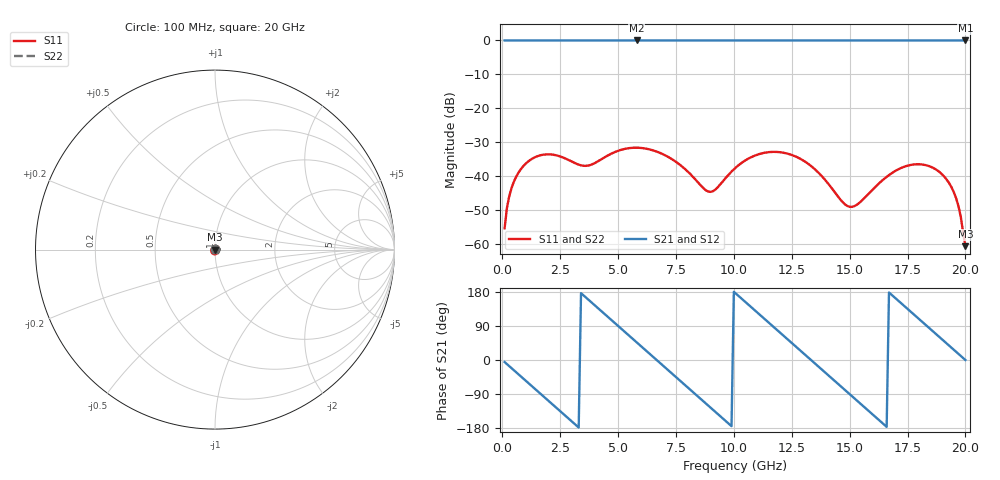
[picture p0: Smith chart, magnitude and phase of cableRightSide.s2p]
! File created by SignalIntegrity v1.5.2: Signal and Power Integrity Tools
! https://github.com/Nubis-Communications/SignalIntegrity
# MHz S MA R 50.0
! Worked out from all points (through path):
!   200 points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, 100 MHz to 20 GHz, reference 50 ohm
!   highest |S21| = 0.00 dB at 20 GHz (marker M1); lowest = 0.0 dB at 5.8 GHz (marker M2)
!   group delay of S21, straight-line fit = 150 ps
!   lowest |S11| = -60.7 dB at 20 GHz (marker M3), VSWR 1.00, Z = 49.9 - j1.12e-17 ohm
!   |S11| at or under -10 dB: start of sweep to end of sweep
!   |S22| runs from -60.7 to -31.7 dB; largest |S21 - S12| = 0
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100  0.00169 84.9  1 -5.4  1 -5.4  0.00169 84.3
600  0.009741 59.6  1 -32.4  1 -32.4  0.009741 55.6
1700  0.02039 6.3  0.9998 -91.8  0.9998 -91.8  0.02039 -9.9
2700  0.01827 -31.6  0.9998 -145.8  0.9998 -145.8  0.01827 -79.9
3500  0.01414 -38.1  0.9999 171.0  0.9999 171.0  0.01414 -159.9
4700  0.02127 -49.7  0.9998 106.2  0.9998 106.2  0.02127 82.1
5800  0.02614 -101.3  0.9997 46.8  0.9997 46.8  0.02614 14.9
6800  0.02199 -160.1  0.9998 -7.2  0.9998 -7.2  0.02199 -34.3
7700  0.01437 144.3  0.9999 -55.8  0.9999 -55.8  0.01437 -75.8
8400  0.008417 110.5  1 -93.6  1 -93.6  0.008417 -117.7
9100  0.005962 116.0  1 -131.4  1 -131.4  0.005962 161.2
10100  0.01346 95.8  0.9999 174.6  0.9999 174.6  0.01346 73.4
11000  0.02054 45.6  0.9998 126.0  0.9998 126.0  0.02054 26.4
11700  0.02269 4.0  0.9997 88.2  0.9997 88.2  0.02269 -7.6
12600  0.01983 -49.9  0.9998 39.6  0.9998 39.6  0.01983 -50.9
13400  0.01346 -97.2  0.9999 -3.6  0.9999 -3.6  0.01346 -90.0
15000  0.003507 -158.1  1 -90.0  1 -90.0  0.003507 158.1
16000  0.006316 160.1  1 -144.0  1 -144.0  0.006316 91.9
16700  0.01031 112.2  0.9999 178.2  0.9999 178.2  0.01031 64.2
18300  0.01441 9.0  0.9999 91.8  0.9999 91.8  0.01441 -5.4
19400  0.006809 -61.8  1 32.4  1 32.4  0.006809 -53.4
20000  0.00092 -180.0  1 0.0  1 0.0  0.00092 -0.0
